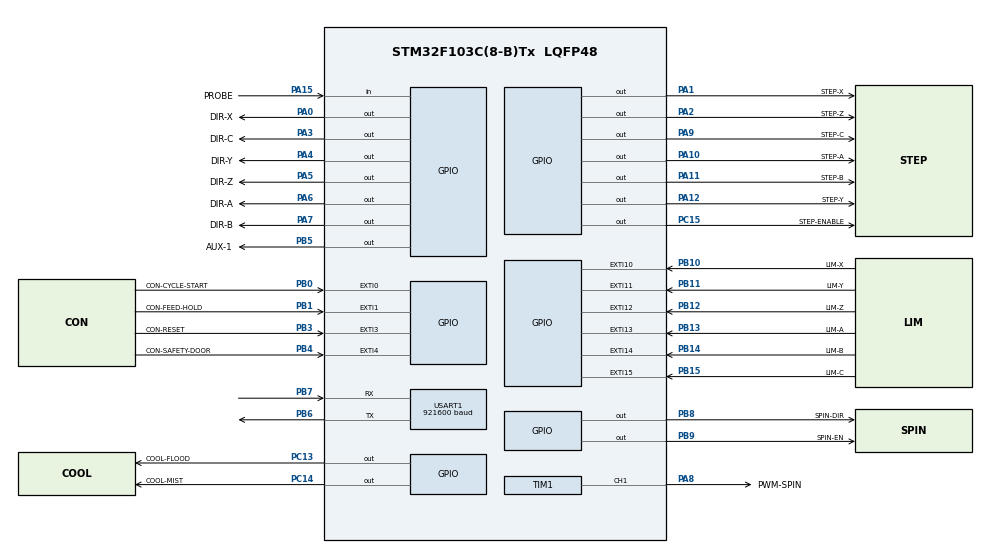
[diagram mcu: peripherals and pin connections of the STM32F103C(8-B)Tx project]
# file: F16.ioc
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Mcu.Family=STM32F1
Mcu.Name=STM32F103C(8-B)Tx
Mcu.Package=LQFP48
NVIC.EXTI0_IRQn=true\:0\:0\:false\:true\:true\:2\:true\:true
NVIC.EXTI15_10_IRQn=true\:0\:0\:false\:false\:true\:true\:true
NVIC.EXTI1_IRQn=true\:0\:0\:false\:true\:true\:3\:true\:true
NVIC.EXTI3_IRQn=true\:0\:0\:false\:true\:true\:4\:true\:true
NVIC.EXTI4_IRQn=true\:0\:0\:false\:true\:true\:5\:true\:true
NVIC.PriorityGroup=NVIC_PRIORITYGROUP_4
NVIC.TIM2_IRQn=true\:0\:0\:false\:false\:true\:true\:true
NVIC.TIM3_IRQn=true\:0\:0\:false\:false\:true\:true\:true
NVIC.USART1_IRQn=true\:0\:0\:false\:true\:true\:1\:true\:true
PA0-WKUP.GPIO_Label=DIR-X
PA0-WKUP.GPIO_Speed=GPIO_SPEED_FREQ_HIGH
PA0-WKUP.Signal=GPIO_Output
PA1.GPIO_Label=STEP-X
PA1.GPIO_Speed=GPIO_SPEED_FREQ_HIGH
PA1.Signal=GPIO_Output
PA10.GPIO_Label=STEP-A
PA10.GPIO_Speed=GPIO_SPEED_FREQ_HIGH
PA10.Signal=GPIO_Output
PA11.GPIO_Label=STEP-B
PA11.GPIO_Speed=GPIO_SPEED_FREQ_HIGH
PA11.Signal=GPIO_Output
PA12.GPIO_Label=STEP-Y
PA12.GPIO_Speed=GPIO_SPEED_FREQ_HIGH
PA12.Signal=GPIO_Output
PA13.Mode=Serial_Wire
PA13.Signal=SYS_JTMS-SWDIO
PA14.Mode=Serial_Wire
PA14.Signal=SYS_JTCK-SWCLK
PA15.GPIO_Label=PROBE
PA15.GPIO_PuPd=GPIO_PULLDOWN
PA15.Signal=GPIO_Input
PA2.GPIO_Label=STEP-Z
PA2.GPIO_Speed=GPIO_SPEED_FREQ_HIGH
PA2.Signal=GPIO_Output
PA3.GPIO_Label=DIR-C
PA3.GPIO_Speed=GPIO_SPEED_FREQ_HIGH
PA3.Signal=GPIO_Output
PA4.GPIO_Label=DIR-Y
PA4.GPIO_Speed=GPIO_SPEED_FREQ_HIGH
PA4.Signal=GPIO_Output
PA5.GPIO_Label=DIR-Z
PA5.GPIO_Speed=GPIO_SPEED_FREQ_HIGH
PA5.Signal=GPIO_Output
PA6.GPIO_Label=DIR-A
PA6.GPIO_Speed=GPIO_SPEED_FREQ_HIGH
PA6.Signal=GPIO_Output
PA7.GPIO_Label=DIR-B
PA7.GPIO_Speed=GPIO_SPEED_FREQ_HIGH
PA7.Signal=GPIO_Output
PA8.GPIO_Label=PWM-SPIN
PA8.Signal=S_TIM1_CH1
PA9.GPIO_Label=STEP-C
PA9.GPIO_Speed=GPIO_SPEED_FREQ_HIGH
PA9.Signal=GPIO_Output
PB0.GPIO_Label=CON-CYCLE-START
PB0.GPIO_ModeDefaultEXTI=GPIO_MODE_IT_FALLING
PB0.GPIO_PuPd=GPIO_PULLUP
PB0.Signal=GPXTI0
PB1.GPIO_Label=CON-FEED-HOLD
PB1.GPIO_ModeDefaultEXTI=GPIO_MODE_IT_FALLING
PB1.GPIO_PuPd=GPIO_PULLUP
PB1.Signal=GPXTI1
PB10.GPIO_Label=LIM-X
PB10.GPIO_ModeDefaultEXTI=GPIO_MODE_IT_FALLING
PB10.GPIO_PuPd=GPIO_PULLUP
PB10.Signal=GPXTI10
PB11.GPIO_Label=LIM-Y
PB11.GPIO_ModeDefaultEXTI=GPIO_MODE_IT_FALLING
PB11.GPIO_PuPd=GPIO_PULLUP
PB11.Signal=GPXTI11
PB12.GPIO_Label=LIM-Z
PB12.GPIO_ModeDefaultEXTI=GPIO_MODE_IT_FALLING
PB12.GPIO_PuPd=GPIO_PULLUP
PB12.Signal=GPXTI12
PB13.GPIO_Label=LIM-A
PB13.GPIO_ModeDefaultEXTI=GPIO_MODE_IT_FALLING
PB13.GPIO_PuPd=GPIO_PULLUP
PB13.Signal=GPXTI13
PB14.GPIO_Label=LIM-B
PB14.GPIO_ModeDefaultEXTI=GPIO_MODE_IT_FALLING
PB14.GPIO_PuPd=GPIO_PULLUP
PB14.Signal=GPXTI14
PB15.GPIO_Label=LIM-C
PB15.GPIO_ModeDefaultEXTI=GPIO_MODE_IT_FALLING
PB15.GPIO_PuPd=GPIO_PULLUP
PB15.Signal=GPXTI15
PB3.GPIO_Label=CON-RESET
PB3.GPIO_ModeDefaultEXTI=GPIO_MODE_IT_FALLING
PB3.GPIO_PuPd=GPIO_PULLUP
PB3.Signal=GPXTI3
PB4.GPIO_Label=CON-SAFETY-DOOR
PB4.GPIO_ModeDefaultEXTI=GPIO_MODE_IT_FALLING
PB4.GPIO_PuPd=GPIO_PULLUP
PB4.Signal=GPXTI4
PB5.GPIO_Label=AUX-1
PB5.GPIO_Speed=GPIO_SPEED_FREQ_HIGH
PB5.Signal=GPIO_Output
PB6.Mode=Asynchronous
PB6.Signal=USART1_TX
PB7.Mode=Asynchronous
PB7.Signal=USART1_RX
PB8.GPIO_Label=SPIN-DIR
PB8.GPIO_Speed=GPIO_SPEED_FREQ_HIGH
PB8.Signal=GPIO_Output
PB9.GPIO_Label=SPIN-EN
PB9.GPIO_Speed=GPIO_SPEED_FREQ_HIGH
PB9.Signal=GPIO_Output
PC13-TAMPER-RTC.GPIO_Label=COOL-FLOOD
PC13-TAMPER-RTC.GPIO_PuPd=GPIO_PULLDOWN
PC13-TAMPER-RTC.GPIO_Speed=GPIO_SPEED_FREQ_HIGH
PC13-TAMPER-RTC.PinState=GPIO_PIN_RESET
PC13-TAMPER-RTC.Signal=GPIO_Output
PC14-OSC32_IN.GPIO_Label=COOL-MIST
PC14-OSC32_IN.GPIO_PuPd=GPIO_PULLDOWN
PC14-OSC32_IN.GPIO_Speed=GPIO_SPEED_FREQ_HIGH
PC14-OSC32_IN.Signal=GPIO_Output
PC15-OSC32_OUT.GPIO_Label=STEP-ENABLE
PC15-OSC32_OUT.GPIO_Speed=GPIO_SPEED_FREQ_HIGH
PC15-OSC32_OUT.PinState=GPIO_PIN_RESET
PC15-OSC32_OUT.Signal=GPIO_Output
PD0-OSC_IN.Mode=HSE-External-Oscillator
PD0-OSC_IN.Signal=RCC_OSC_IN
PD1-OSC_OUT.Mode=HSE-External-Oscillator
PD1-OSC_OUT.Signal=RCC_OSC_OUT
ProjectManager.HeapSize=0x200
ProjectManager.StackSize=0x400
ProjectManager.TargetToolchain=TrueSTUDIO
RCC.AHBFreq_Value=72000000
RCC.APB1CLKDivider=RCC_HCLK_DIV2
RCC.APB1Freq_Value=36000000
RCC.APB1TimFreq_Value=72000000
RCC.APB2Freq_Value=72000000
RCC.APB2TimFreq_Value=72000000
RCC.HCLKFreq_Value=72000000
RCC.PLLMUL=RCC_PLL_MUL9
RCC.PLLSourceVirtual=RCC_PLLSOURCE_HSE
RCC.SYSCLKFreq_VALUE=72000000
RCC.SYSCLKSource=RCC_SYSCLKSOURCE_PLLCLK
RCC.USBFreq_Value=72000000
SH.S_TIM1_CH1.0=TIM1_CH1,PWM Generation1 CH1
TIM1.Channel-PWM\ Generation1\ CH1=TIM_CHANNEL_1
TIM1.Period=7199
USART1.BaudRate=921600
USART1.VirtualMode=VM_ASYNC
VP_TIM2_VS_ClockSourceINT.Mode=Internal
VP_TIM3_VS_ClockSourceINT.Mode=Internal
board=F103C8

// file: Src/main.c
/* USER CODE BEGIN Header */
/**
  ******************************************************************************
  * @file           : main.c
  * @brief          : Main program body
  ******************************************************************************
  ** This notice applies to any and all portions of this file
  * that are not between comment pairs USER CODE BEGIN and
  * USER CODE END. Other portions of this file, whether
  * inserted by the user or by software development tools
  * are owned by their respective copyright owners.
  *
  * COPYRIGHT(c) 2019 STMicroelectronics
  * Copyright (c) 2018-2019 Thomas Truong
  *
  * Redistribution and use in source and binary forms, with or without modification,
  * are permitted provided that the following conditions are met:
  *   1. Redistributions of source code must retain the above copyright notice,
  *      this list of conditions and the following disclaimer.
  *   2. Redistributions in binary form must reproduce the above copyright notice,
  *      this list of conditions and the following disclaimer in the documentation
  *      and/or other materials provided with the distribution.
  *   3. Neither the name of STMicroelectronics nor the names of its contributors
  *      may be used to endorse or promote products derived from this software
  *      without specific prior written permission.
  *
  * THIS SOFTWARE IS PROVIDED BY THE COPYRIGHT HOLDERS AND CONTRIBUTORS "AS IS"
  * AND ANY EXPRESS OR IMPLIED WARRANTIES, INCLUDING, BUT NOT LIMITED TO, THE
  * IMPLIED WARRANTIES OF MERCHANTABILITY AND FITNESS FOR A PARTICULAR PURPOSE ARE
  * DISCLAIMED. IN NO EVENT SHALL THE COPYRIGHT HOLDER OR CONTRIBUTORS BE LIABLE
  * FOR ANY DIRECT, INDIRECT, INCIDENTAL, SPECIAL, EXEMPLARY, OR CONSEQUENTIAL
  * DAMAGES (INCLUDING, BUT NOT LIMITED TO, PROCUREMENT OF SUBSTITUTE GOODS OR
  * SERVICES; LOSS OF USE, DATA, OR PROFITS; OR BUSINESS INTERRUPTION) HOWEVER
  * CAUSED AND ON ANY THEORY OF LIABILITY, WHETHER IN CONTRACT, STRICT LIABILITY,
  * OR TORT (INCLUDING NEGLIGENCE OR OTHERWISE) ARISING IN ANY WAY OUT OF THE USE
  * OF THIS SOFTWARE, EVEN IF ADVISED OF THE POSSIBILITY OF SUCH DAMAGE.
  *
  ******************************************************************************
  */
/* USER CODE END Header */

#include "main.h"
#include "tim.h"
#include "usart.h"
#include "gpio.h"

/* USER CODE BEGIN Includes */

#include "grbl.h"

/* USER CODE END Includes */

/* USER CODE BEGIN PV */

system_t sys;
int32_t sys_position[N_AXIS];      // Real-time machine (aka home) position vector in steps.
int32_t sys_probe_position[N_AXIS]; // Last probe position in machine coordinates and steps.
volatile uint8_t sys_probe_state;   // Probing state value.  Used to coordinate the probing cycle with stepper ISR.
volatile uint8_t sys_rt_exec_state;   // Global realtime executor bitflag variable for state management. See EXEC bitmasks.
volatile uint8_t sys_rt_exec_alarm;   // Global realtime executor bitflag variable for setting various alarms.
volatile uint8_t sys_rt_exec_motion_override; // Global realtime executor bitflag variable for motion-based overrides.
volatile uint8_t sys_rt_exec_accessory_override; // Global realtime executor bitflag variable for spindle/coolant overrides.
#ifdef DEBUG
  volatile uint8_t sys_rt_exec_debug;
#endif

/* USER CODE END PV */

void SystemClock_Config(void);
static void MX_NVIC_Init(void);

int main(void)
{

  /* MCU Configuration--------------------------------------------------------*/

  /* Reset of all peripherals, Initializes the Flash interface and the Systick. */
  HAL_Init();

  /* Configure the system clock */
  SystemClock_Config();

  /* Initialize all configured peripherals */
  MX_GPIO_Init();
  MX_TIM1_Init();
  MX_USART1_UART_Init();
  MX_TIM2_Init();
  MX_TIM3_Init();

  /* Initialize interrupts */
  MX_NVIC_Init();
  /* USER CODE BEGIN 2 */

  timing_init();
  uart_init();

  eeprom_init();
  serial_init();   // Setup serial baud rate and interrupts
  settings_init(); // Load Grbl settings from EEPROM
  stepper_init();  // Configure stepper pins and interrupt timers
  system_init();   // Configure pinout pins and pin-change interrupt
  memset(sys_position,0,sizeof(sys_position)); // Clear machine position.

  // Initialize system state.
  #ifdef FORCE_INITIALIZATION_ALARM
    // Force Grbl into an ALARM state upon a power-cycle or hard reset.
    sys.state = STATE_ALARM;
  #else
    sys.state = STATE_IDLE;
  #endif

  // Check for power-up and set system alarm if homing is enabled to force homing cycle
  // by setting Grbl's alarm state. Alarm locks out all g-code commands, including the
  // startup scripts, but allows access to settings and internal commands. Only a homing
  // cycle '$H' or kill alarm locks '$X' will disable the alarm.
  // NOTE: The startup script will run after successful completion of the homing cycle, but
  // not after disabling the alarm locks. Prevents motion startup blocks from crashing into
  // things uncontrollably. Very bad.
  #ifdef HOMING_INIT_LOCK
    if (bit_istrue(settings.flags,BITFLAG_HOMING_ENABLE)) { sys.state = STATE_ALARM; }
  #endif

  /* USER CODE END 2 */

  /* Infinite loop */
  /* USER CODE BEGIN WHILE */
  while (1)
  {

	// Reset system variables.
	uint8_t prior_state = sys.state;
	memset(&sys, 0, sizeof(system_t)); // Clear system struct variable.
	sys.state = prior_state;
	sys.f_override = DEFAULT_FEED_OVERRIDE;  // Set to 100%
	sys.r_override = DEFAULT_RAPID_OVERRIDE; // Set to 100%
	sys.spindle_speed_ovr = DEFAULT_SPINDLE_SPEED_OVERRIDE; // Set to 100%
		memset(sys_probe_position,0,sizeof(sys_probe_position)); // Clear probe position.
	sys_probe_state = 0;
	sys_rt_exec_state = 0;
	sys_rt_exec_alarm = 0;
	sys_rt_exec_motion_override = 0;
	sys_rt_exec_accessory_override = 0;

	// Reset Grbl primary systems.
	serial_reset_read_buffer(); // Clear serial read buffer
	gc_init(); // Set g-code parser to default state
	spindle_init();
	coolant_init();
	limits_init();
	probe_init();
	inoutputs_init();

	plan_reset(); // Clear block buffer and planner variables
	st_reset(); // Clear stepper subsystem variables.

	// Sync cleared gcode and planner positions to current system position.
	plan_sync_position();
	gc_sync_position();

	// Print welcome message. Indicates an initialization has occured at power-up or with a reset.
	report_init_message();

	// Start Grbl main loop. Processes program inputs and executes them.
	protocol_main_loop();

    /* USER CODE END WHILE */

  }
}

void SystemClock_Config(void)
{
  RCC_OscInitTypeDef RCC_OscInitStruct = {0};
  RCC_ClkInitTypeDef RCC_ClkInitStruct = {0};

  /** Initializes the CPU, AHB and APB busses clocks
  */
  RCC_OscInitStruct.OscillatorType = RCC_OSCILLATORTYPE_HSE;
  RCC_OscInitStruct.HSEState = RCC_HSE_ON;
  RCC_OscInitStruct.HSEPredivValue = RCC_HSE_PREDIV_DIV1;
  RCC_OscInitStruct.HSIState = RCC_HSI_ON;
  RCC_OscInitStruct.PLL.PLLState = RCC_PLL_ON;
  RCC_OscInitStruct.PLL.PLLSource = RCC_PLLSOURCE_HSE;
  RCC_OscInitStruct.PLL.PLLMUL = RCC_PLL_MUL12;//RCC_PLL_MUL12;//RCC_PLL_MUL9;
  if (HAL_RCC_OscConfig(&RCC_OscInitStruct) != HAL_OK)
  {
    Error_Handler();
  }
  /** Initializes the CPU, AHB and APB busses clocks
  */
  RCC_ClkInitStruct.ClockType = RCC_CLOCKTYPE_HCLK|RCC_CLOCKTYPE_SYSCLK
                              |RCC_CLOCKTYPE_PCLK1|RCC_CLOCKTYPE_PCLK2;
  RCC_ClkInitStruct.SYSCLKSource = RCC_SYSCLKSOURCE_PLLCLK;
  RCC_ClkInitStruct.AHBCLKDivider = RCC_SYSCLK_DIV1;
  RCC_ClkInitStruct.APB1CLKDivider = RCC_HCLK_DIV2;
  RCC_ClkInitStruct.APB2CLKDivider = RCC_HCLK_DIV1;

  if (HAL_RCC_ClockConfig(&RCC_ClkInitStruct, FLASH_LATENCY_2) != HAL_OK)
  {
    Error_Handler();
  }
}

/**
  * @brief NVIC Configuration.
  * @retval None
  */
static void MX_NVIC_Init(void)
{
  /* USART1_IRQn interrupt configuration */
  NVIC_SetPriority(USART1_IRQn, NVIC_EncodePriority(NVIC_GetPriorityGrouping(),0, 0));
  NVIC_EnableIRQ(USART1_IRQn);
  /* EXTI0_IRQn interrupt configuration */
  HAL_NVIC_SetPriority(EXTI0_IRQn, 0, 0);
  HAL_NVIC_EnableIRQ(EXTI0_IRQn);
  /* EXTI1_IRQn interrupt configuration */
  HAL_NVIC_SetPriority(EXTI1_IRQn, 0, 0);
  HAL_NVIC_EnableIRQ(EXTI1_IRQn);
  /* EXTI3_IRQn interrupt configuration */
  HAL_NVIC_SetPriority(EXTI3_IRQn, 0, 0);
  HAL_NVIC_EnableIRQ(EXTI3_IRQn);
  /* EXTI4_IRQn interrupt configuration */
  HAL_NVIC_SetPriority(EXTI4_IRQn, 0, 0);
  HAL_NVIC_EnableIRQ(EXTI4_IRQn);
}

void Error_Handler(void)
{
}

/************************ (C) COPYRIGHT STMicroelectronics *****END OF FILE****/
